VERSION 5.7 ;
  NOWIREEXTENSIONATPIN ON ;
  DIVIDERCHAR "/" ;
  BUSBITCHARS "[]" ;
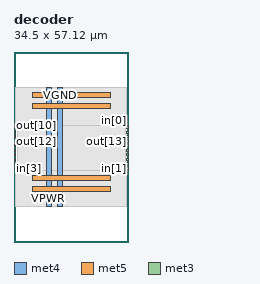
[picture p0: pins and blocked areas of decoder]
MACRO decoder
  CLASS BLOCK ;
  FOREIGN decoder ;
  ORIGIN 0.000 0.000 ;
  SIZE 34.500 BY 57.120 ;
  PIN VGND
    DIRECTION INOUT ;
    USE GROUND ;
    PORT
      LAYER met4 ;
        RECT 13.020 10.640 14.620 46.480 ;
    END
    PORT
      LAYER met5 ;
        RECT 5.520 18.380 28.980 19.980 ;
    END
    PORT
      LAYER met5 ;
        RECT 5.520 43.380 28.980 44.980 ;
    END
  END VGND
  PIN VPWR
    DIRECTION INOUT ;
    USE POWER ;
    PORT
      LAYER met4 ;
        RECT 9.720 10.640 11.320 46.480 ;
    END
    PORT
      LAYER met5 ;
        RECT 5.520 15.080 28.980 16.680 ;
    END
    PORT
      LAYER met5 ;
        RECT 5.520 40.080 28.980 41.680 ;
    END
  END VPWR
  PIN in[0]
    DIRECTION INPUT ;
    USE SIGNAL ;
    ANTENNAGATEAREA 0.213000 ;
    PORT
      LAYER met3 ;
        RECT 33.900 34.040 34.500 34.640 ;
    END
  END in[0]
  PIN in[1]
    DIRECTION INPUT ;
    USE SIGNAL ;
    ANTENNAGATEAREA 0.213000 ;
    PORT
      LAYER met3 ;
        RECT 33.900 21.800 34.500 22.400 ;
    END
  END in[1]
  PIN in[2]
    DIRECTION INPUT ;
    USE SIGNAL ;
    ANTENNAGATEAREA 0.213000 ;
    PORT
      LAYER met3 ;
        RECT 33.900 23.160 34.500 23.760 ;
    END
  END in[2]
  PIN in[3]
    DIRECTION INPUT ;
    USE SIGNAL ;
    ANTENNAGATEAREA 0.213000 ;
    PORT
      LAYER met3 ;
        RECT 0.000 21.800 0.600 22.400 ;
    END
  END in[3]
  PIN out[0]
    DIRECTION OUTPUT ;
    USE SIGNAL ;
    ANTENNADIFFAREA 0.702900 ;
    PORT
      LAYER met3 ;
        RECT 33.900 27.240 34.500 27.840 ;
    END
  END out[0]
  PIN out[10]
    DIRECTION OUTPUT ;
    USE SIGNAL ;
    ANTENNADIFFAREA 0.702900 ;
    PORT
      LAYER met3 ;
        RECT 0.000 32.680 0.600 33.280 ;
    END
  END out[10]
  PIN out[11]
    DIRECTION OUTPUT ;
    USE SIGNAL ;
    ANTENNADIFFAREA 0.702900 ;
    PORT
      LAYER met3 ;
        RECT 33.900 32.680 34.500 33.280 ;
    END
  END out[11]
  PIN out[12]
    DIRECTION OUTPUT ;
    USE SIGNAL ;
    ANTENNADIFFAREA 0.702900 ;
    PORT
      LAYER met3 ;
        RECT 0.000 29.960 0.600 30.560 ;
    END
  END out[12]
  PIN out[13]
    DIRECTION OUTPUT ;
    USE SIGNAL ;
    ANTENNADIFFAREA 0.702900 ;
    PORT
      LAYER met3 ;
        RECT 33.900 29.960 34.500 30.560 ;
    END
  END out[13]
  PIN out[14]
    DIRECTION OUTPUT ;
    USE SIGNAL ;
    ANTENNADIFFAREA 0.702900 ;
    PORT
      LAYER met3 ;
        RECT 33.900 28.600 34.500 29.200 ;
    END
  END out[14]
  PIN out[15]
    DIRECTION OUTPUT ;
    USE SIGNAL ;
    ANTENNADIFFAREA 0.702900 ;
    PORT
      LAYER met3 ;
        RECT 33.900 24.520 34.500 25.120 ;
    END
  END out[15]
  PIN out[1]
    DIRECTION OUTPUT ;
    USE SIGNAL ;
    ANTENNADIFFAREA 0.702900 ;
    PORT
      LAYER met3 ;
        RECT 0.000 24.520 0.600 25.120 ;
    END
  END out[1]
  PIN out[2]
    DIRECTION OUTPUT ;
    USE SIGNAL ;
    ANTENNADIFFAREA 0.702900 ;
    PORT
      LAYER met3 ;
        RECT 0.000 25.880 0.600 26.480 ;
    END
  END out[2]
  PIN out[3]
    DIRECTION OUTPUT ;
    USE SIGNAL ;
    ANTENNADIFFAREA 0.702900 ;
    PORT
      LAYER met3 ;
        RECT 0.000 23.160 0.600 23.760 ;
    END
  END out[3]
  PIN out[4]
    DIRECTION OUTPUT ;
    USE SIGNAL ;
    ANTENNADIFFAREA 0.702900 ;
    PORT
      LAYER met3 ;
        RECT 0.000 27.240 0.600 27.840 ;
    END
  END out[4]
  PIN out[5]
    DIRECTION OUTPUT ;
    USE SIGNAL ;
    ANTENNADIFFAREA 0.702900 ;
    PORT
      LAYER met3 ;
        RECT 0.000 34.040 0.600 34.640 ;
    END
  END out[5]
  PIN out[6]
    DIRECTION OUTPUT ;
    USE SIGNAL ;
    ANTENNADIFFAREA 0.702900 ;
    PORT
      LAYER met3 ;
        RECT 0.000 28.600 0.600 29.200 ;
    END
  END out[6]
  PIN out[7]
    DIRECTION OUTPUT ;
    USE SIGNAL ;
    ANTENNADIFFAREA 0.702900 ;
    PORT
      LAYER met3 ;
        RECT 33.900 31.320 34.500 31.920 ;
    END
  END out[7]
  PIN out[8]
    DIRECTION OUTPUT ;
    USE SIGNAL ;
    ANTENNADIFFAREA 0.702900 ;
    PORT
      LAYER met3 ;
        RECT 33.900 25.880 34.500 26.480 ;
    END
  END out[8]
  PIN out[9]
    DIRECTION OUTPUT ;
    USE SIGNAL ;
    ANTENNADIFFAREA 0.702900 ;
    PORT
      LAYER met3 ;
        RECT 0.000 31.320 0.600 31.920 ;
    END
  END out[9]
  OBS
      LAYER nwell ;
        RECT 5.330 10.795 29.170 46.430 ;
      LAYER li1 ;
        RECT 5.520 10.795 28.980 46.325 ;
      LAYER met1 ;
        RECT 3.750 10.640 32.130 46.480 ;
      LAYER met2 ;
        RECT 3.770 10.695 32.110 46.425 ;
      LAYER met3 ;
        RECT 0.600 35.040 33.900 46.405 ;
        RECT 1.000 21.400 33.500 35.040 ;
        RECT 0.600 10.715 33.900 21.400 ;
  END
END decoder
END LIBRARY

